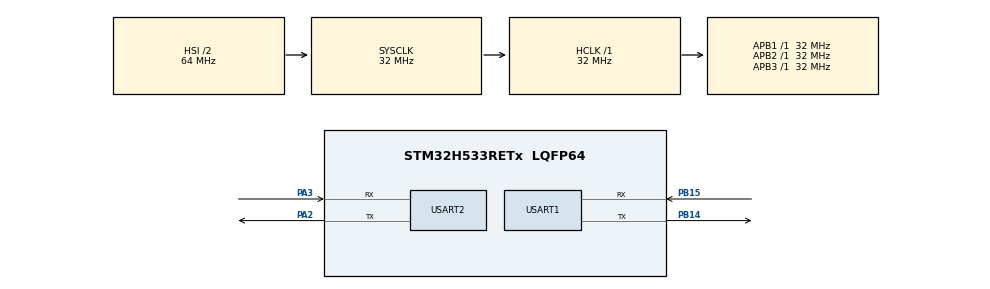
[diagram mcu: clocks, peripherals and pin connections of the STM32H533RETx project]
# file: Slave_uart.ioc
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CORTEX_M33_NS.userName=CORTEX_M33
Mcu.Family=STM32H5
Mcu.Name=STM32H533RETx
Mcu.Package=LQFP64
NVIC.PriorityGroup=NVIC_PRIORITYGROUP_4
NVIC.USART1_IRQn=true\:0\:0\:false\:false\:true\:true\:true\:true
PA2.Mode=Asynchronous
PA2.Signal=USART2_TX
PA3.Mode=Asynchronous
PA3.Signal=USART2_RX
PB14.Mode=Asynchronous
PB14.Signal=USART1_TX
PB15.Mode=Asynchronous
PB15.Signal=USART1_RX
ProjectManager.HeapSize=0x200
ProjectManager.StackSize=0x400
ProjectManager.TargetToolchain=STM32CubeIDE
RCC.ADCFreq_Value=32000000
RCC.AHBFreq_Value=32000000
RCC.APB1Freq_Value=32000000
RCC.APB1TimFreq_Value=32000000
RCC.APB2Freq_Value=32000000
RCC.APB2TimFreq_Value=32000000
RCC.APB3Freq_Value=32000000
RCC.CSI_VALUE=4000000
RCC.CortexFreq_Value=32000000
RCC.EPOD_VALUE=4000000
RCC.HCLKFreq_Value=32000000
RCC.HSE_VALUE=25000000
RCC.HSI48_VALUE=48000000
RCC.HSI_VALUE=64000000
RCC.LSE_VALUE=32768
RCC.LSIRC_VALUE=32000
RCC.SYSCLKFreq_VALUE=32000000
RCC.USBFreq_Value=48000000
RCC.VCOOutputFreq_Value=516000000
USART1.VirtualMode-Asynchronous=VM_ASYNC
USART2.VirtualMode-Asynchronous=VM_ASYNC
VP_BOOTPATH_VS_BOOTPATH.Mode=BP_Activate
VP_CORTEX_M33_NS_VS_Hclk.Mode=Hclk_Mode
VP_MEMORYMAP_VS_MEMORYMAP.Mode=CurAppReg
VP_PWR_VS_LPOM.Mode=PowerOptimisation
VP_PWR_VS_SECSignals.Mode=Security/Privilege
board=NUCLEO-H533RE

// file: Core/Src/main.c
/* USER CODE BEGIN Header */
/**
  ******************************************************************************
  * @file           : main.c
  * @brief          : Main program body
  ******************************************************************************
  * @attention
  *
  * Copyright (c) 2025 STMicroelectronics.
  * All rights reserved.
  *
  * This software is licensed under terms that can be found in the LICENSE file
  * in the root directory of this software component.
  * If no LICENSE file comes with this software, it is provided AS-IS.
  *
  ******************************************************************************
  */
/* USER CODE END Header */
#include "main.h"
#include <stdio.h>
#include <string.h>
#include <stdlib.h>

/* USER CODE BEGIN PTD */
volatile uint8_t DataFlag = 0;
uint16_t received_adc = 0;  // Stores received ADC value from other board
uint8_t rx_buffer[10];      // Buffer for receiving ADC string
uint8_t rx_index = 0;

/* USER CODE END PTD */

UART_HandleTypeDef huart1;
UART_HandleTypeDef huart2;

void SystemClock_Config(void);
static void MX_GPIO_Init(void);
static void MX_USART1_UART_Init(void);
static void MX_USART2_UART_Init(void);

/* USER CODE BEGIN 0 */
void HAL_UART_RxCpltCallback(UART_HandleTypeDef *huart) {
  if (huart == &huart1) {
    // Check for terminator
    if (rx_buffer[rx_index] == '\n') {
      rx_buffer[rx_index] = '\0'; // Null-terminate
      received_adc = (uint16_t)atoi((char*)rx_buffer);
      DataFlag = 1;
      rx_index = 0; // Reset index after processing
      return;
    } else {
      // Prevent buffer overflow
      if (rx_index < sizeof(rx_buffer) - 1) {
        rx_index++; // Only increment if space remains
      } else {
        rx_index = 0; // Reset on overflow
      }
    }
    // Restart reception
    HAL_UART_Receive_IT(&huart1, &rx_buffer[rx_index], 1);
  }
}

/* USER CODE END 0 */

int main(void)
{

  /* MCU Configuration--------------------------------------------------------*/

  /* Reset of all peripherals, Initializes the Flash interface and the Systick. */
  HAL_Init();

  /* Configure the system clock */
  SystemClock_Config();

  /* Initialize all configured peripherals */
  MX_GPIO_Init();
  MX_USART1_UART_Init();
  MX_USART2_UART_Init();
  /* USER CODE BEGIN 2 */
  HAL_UART_Receive_IT(&huart1, &rx_buffer[0], 1);
  //HAL_UART_Receive_IT(&huart1, rx_buffer, sizeof(rx_buffer)); // Restart UART reception
  //HAL_UART_Transmit(&huart2, (uint8_t*)rx_buffer, strlen(rx_buffer), HAL_MAX_DELAY);

  /* USER CODE END 2 */

  /* Infinite loop */
  /* USER CODE BEGIN WHILE */
  while (1)
  {
	if (DataFlag) {  // New ADC value received
	  DataFlag = 0;

	  // Example: Print received ADC value via USART2
	  char debug_msg[20];
	  sprintf(debug_msg, "Received: %hu\r\n", received_adc);
	  HAL_UART_Transmit(&huart2, (uint8_t*)debug_msg, strlen(debug_msg), HAL_MAX_DELAY);
	  HAL_UART_Receive_IT(&huart1, &rx_buffer[0], 1);

	}

    /* USER CODE END WHILE */

  }
}

void SystemClock_Config(void)
{
  RCC_OscInitTypeDef RCC_OscInitStruct = {0};
  RCC_ClkInitTypeDef RCC_ClkInitStruct = {0};

  /** Configure the main internal regulator output voltage
  */
  __HAL_PWR_VOLTAGESCALING_CONFIG(PWR_REGULATOR_VOLTAGE_SCALE3);

  while(!__HAL_PWR_GET_FLAG(PWR_FLAG_VOSRDY)) {}

  /** Initializes the RCC Oscillators according to the specified parameters
  * in the RCC_OscInitTypeDef structure.
  */
  RCC_OscInitStruct.OscillatorType = RCC_OSCILLATORTYPE_HSI;
  RCC_OscInitStruct.HSIState = RCC_HSI_ON;
  RCC_OscInitStruct.HSIDiv = RCC_HSI_DIV2;
  RCC_OscInitStruct.HSICalibrationValue = RCC_HSICALIBRATION_DEFAULT;
  RCC_OscInitStruct.PLL.PLLState = RCC_PLL_NONE;
  if (HAL_RCC_OscConfig(&RCC_OscInitStruct) != HAL_OK)
  {
    Error_Handler();
  }

  /** Initializes the CPU, AHB and APB buses clocks
  */
  RCC_ClkInitStruct.ClockType = RCC_CLOCKTYPE_HCLK|RCC_CLOCKTYPE_SYSCLK
                              |RCC_CLOCKTYPE_PCLK1|RCC_CLOCKTYPE_PCLK2
                              |RCC_CLOCKTYPE_PCLK3;
  RCC_ClkInitStruct.SYSCLKSource = RCC_SYSCLKSOURCE_HSI;
  RCC_ClkInitStruct.AHBCLKDivider = RCC_SYSCLK_DIV1;
  RCC_ClkInitStruct.APB1CLKDivider = RCC_HCLK_DIV1;
  RCC_ClkInitStruct.APB2CLKDivider = RCC_HCLK_DIV1;
  RCC_ClkInitStruct.APB3CLKDivider = RCC_HCLK_DIV1;

  if (HAL_RCC_ClockConfig(&RCC_ClkInitStruct, FLASH_LATENCY_1) != HAL_OK)
  {
    Error_Handler();
  }

  /** Configure the programming delay
  */
  __HAL_FLASH_SET_PROGRAM_DELAY(FLASH_PROGRAMMING_DELAY_0);
}

static void MX_USART1_UART_Init(void)
{

  huart1.Instance = USART1;
  huart1.Init.BaudRate = 115200;
  huart1.Init.WordLength = UART_WORDLENGTH_8B;
  huart1.Init.StopBits = UART_STOPBITS_1;
  huart1.Init.Parity = UART_PARITY_NONE;
  huart1.Init.Mode = UART_MODE_TX_RX;
  huart1.Init.HwFlowCtl = UART_HWCONTROL_NONE;
  huart1.Init.OverSampling = UART_OVERSAMPLING_16;
  huart1.Init.OneBitSampling = UART_ONE_BIT_SAMPLE_DISABLE;
  huart1.Init.ClockPrescaler = UART_PRESCALER_DIV1;
  huart1.AdvancedInit.AdvFeatureInit = UART_ADVFEATURE_NO_INIT;
  if (HAL_UART_Init(&huart1) != HAL_OK)
  {
    Error_Handler();
  }
  if (HAL_UARTEx_SetTxFifoThreshold(&huart1, UART_TXFIFO_THRESHOLD_1_8) != HAL_OK)
  {
    Error_Handler();
  }
  if (HAL_UARTEx_SetRxFifoThreshold(&huart1, UART_RXFIFO_THRESHOLD_1_8) != HAL_OK)
  {
    Error_Handler();
  }
  if (HAL_UARTEx_DisableFifoMode(&huart1) != HAL_OK)
  {
    Error_Handler();
  }

}

static void MX_USART2_UART_Init(void)
{

  huart2.Instance = USART2;
  huart2.Init.BaudRate = 115200;
  huart2.Init.WordLength = UART_WORDLENGTH_8B;
  huart2.Init.StopBits = UART_STOPBITS_1;
  huart2.Init.Parity = UART_PARITY_NONE;
  huart2.Init.Mode = UART_MODE_TX_RX;
  huart2.Init.HwFlowCtl = UART_HWCONTROL_NONE;
  huart2.Init.OverSampling = UART_OVERSAMPLING_16;
  huart2.Init.OneBitSampling = UART_ONE_BIT_SAMPLE_DISABLE;
  huart2.Init.ClockPrescaler = UART_PRESCALER_DIV1;
  huart2.AdvancedInit.AdvFeatureInit = UART_ADVFEATURE_NO_INIT;
  if (HAL_UART_Init(&huart2) != HAL_OK)
  {
    Error_Handler();
  }
  if (HAL_UARTEx_SetTxFifoThreshold(&huart2, UART_TXFIFO_THRESHOLD_1_8) != HAL_OK)
  {
    Error_Handler();
  }
  if (HAL_UARTEx_SetRxFifoThreshold(&huart2, UART_RXFIFO_THRESHOLD_1_8) != HAL_OK)
  {
    Error_Handler();
  }
  if (HAL_UARTEx_DisableFifoMode(&huart2) != HAL_OK)
  {
    Error_Handler();
  }

}

static void MX_GPIO_Init(void)
{
  GPIO_InitTypeDef GPIO_InitStruct = {0};

  /* GPIO Ports Clock Enable */
  __HAL_RCC_GPIOC_CLK_ENABLE();
  __HAL_RCC_GPIOA_CLK_ENABLE();
  __HAL_RCC_GPIOB_CLK_ENABLE();

  /*Configure GPIO pin Output Level */
  HAL_GPIO_WritePin(GPIOA, GPIO_PIN_5, GPIO_PIN_RESET);

  /*Configure GPIO pin : PC13 */
  GPIO_InitStruct.Pin = GPIO_PIN_13;
  GPIO_InitStruct.Mode = GPIO_MODE_IT_RISING;
  GPIO_InitStruct.Pull = GPIO_NOPULL;
  HAL_GPIO_Init(GPIOC, &GPIO_InitStruct);

  /*Configure GPIO pin : PA5 */
  GPIO_InitStruct.Pin = GPIO_PIN_5;
  GPIO_InitStruct.Mode = GPIO_MODE_OUTPUT_PP;
  GPIO_InitStruct.Pull = GPIO_NOPULL;
  GPIO_InitStruct.Speed = GPIO_SPEED_FREQ_LOW;
  HAL_GPIO_Init(GPIOA, &GPIO_InitStruct);

  /*Configure GPIO pin : PC4 */
  GPIO_InitStruct.Pin = GPIO_PIN_4;
  GPIO_InitStruct.Mode = GPIO_MODE_INPUT;
  GPIO_InitStruct.Pull = GPIO_NOPULL;
  HAL_GPIO_Init(GPIOC, &GPIO_InitStruct);

}

void Error_Handler(void)
{
  __disable_irq();
  while (1)
  {
  }
}
